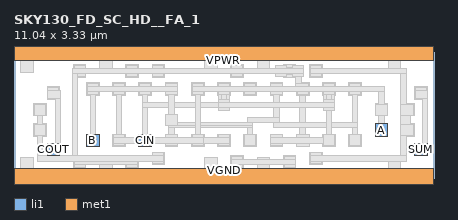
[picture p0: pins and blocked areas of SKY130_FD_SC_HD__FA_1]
MACRO SKY130_FD_SC_HD__FA_1
 CLASS CORE ;
 FOREIGN SKY130_FD_SC_HD__FA_1 0 0 ;
 SIZE 11.040000000000001 BY 3.33 ;
 ORIGIN 0 0 ;
 SYMMETRY X Y R90 ;
 SITE unit ;
  PIN VPWR
   DIRECTION INOUT ;
   USE POWER ;
   SHAPE ABUTMENT ;
    PORT
     CLASS CORE ;
       LAYER li1 ;
        RECT 0.00000000 3.09000000 11.04000000 3.57000000 ;
       LAYER met1 ;
        RECT 0.00000000 3.09000000 11.04000000 3.57000000 ;
    END
  END VPWR

  PIN VGND
   DIRECTION INOUT ;
   USE POWER ;
   SHAPE ABUTMENT ;
    PORT
     CLASS CORE ;
       LAYER li1 ;
        RECT 0.00000000 -0.24000000 11.04000000 0.24000000 ;
       LAYER met1 ;
        RECT 0.00000000 -0.24000000 11.04000000 0.24000000 ;
    END
  END VGND

  PIN COUT
   DIRECTION INOUT ;
   USE SIGNAL ;
   SHAPE ABUTMENT ;
    PORT
     CLASS CORE ;
       LAYER li1 ;
        RECT 0.87000000 0.58000000 1.20000000 0.91000000 ;
    END
  END COUT

  PIN SUM
   DIRECTION INOUT ;
   USE SIGNAL ;
   SHAPE ABUTMENT ;
    PORT
     CLASS CORE ;
       LAYER li1 ;
        RECT 10.53000000 0.58000000 10.86000000 0.91000000 ;
    END
  END SUM

  PIN A
   DIRECTION INOUT ;
   USE SIGNAL ;
   SHAPE ABUTMENT ;
    PORT
     CLASS CORE ;
       LAYER li1 ;
        RECT 9.49500000 1.09500000 9.82500000 1.42500000 ;
    END
  END A

  PIN B
   DIRECTION INOUT ;
   USE SIGNAL ;
   SHAPE ABUTMENT ;
    PORT
     CLASS CORE ;
       LAYER li1 ;
        RECT 1.90500000 0.82500000 2.23500000 1.15500000 ;
    END
  END B

  PIN CIN
   DIRECTION INOUT ;
   USE SIGNAL ;
   SHAPE ABUTMENT ;
    PORT
     CLASS CORE ;
       LAYER li1 ;
        RECT 3.28500000 0.82500000 3.61500000 1.15500000 ;
    END
  END CIN

 OBS
    LAYER polycont ;
     RECT 3.36500000 0.90500000 3.53500000 1.07500000 ;
     RECT 6.81500000 0.90500000 6.98500000 1.07500000 ;
     RECT 8.19500000 0.90500000 8.36500000 1.07500000 ;
     RECT 3.36500000 2.25500000 3.53500000 2.42500000 ;
     RECT 5.43500000 2.25500000 5.60500000 2.42500000 ;
     RECT 8.19500000 2.25500000 8.36500000 2.42500000 ;
     RECT 1.98500000 0.90500000 2.15500000 1.07500000 ;
     RECT 4.05500000 0.90500000 4.22500000 1.07500000 ;
     RECT 6.12500000 0.90500000 6.29500000 1.07500000 ;
     RECT 8.88500000 0.90500000 9.05500000 1.07500000 ;
     RECT 1.98500000 2.25500000 2.15500000 2.42500000 ;
     RECT 4.05500000 2.25500000 4.22500000 2.42500000 ;
     RECT 6.81500000 2.25500000 6.98500000 2.42500000 ;
     RECT 8.88500000 2.25500000 9.05500000 2.42500000 ;
     RECT 7.50500000 0.90500000 7.67500000 1.07500000 ;
     RECT 0.60500000 1.17500000 0.77500000 1.34500000 ;
     RECT 0.60500000 1.71500000 0.77500000 1.88500000 ;
     RECT 7.50500000 2.25500000 7.67500000 2.42500000 ;
     RECT 10.26500000 1.17500000 10.43500000 1.34500000 ;
     RECT 10.26500000 1.71500000 10.43500000 1.88500000 ;
     RECT 2.67500000 0.90500000 2.84500000 1.07500000 ;
     RECT 4.74500000 0.90500000 4.91500000 1.07500000 ;
     RECT 5.43500000 0.90500000 5.60500000 1.07500000 ;
     RECT 9.57500000 1.17500000 9.74500000 1.34500000 ;
     RECT 9.57500000 1.71500000 9.74500000 1.88500000 ;
     RECT 2.67500000 2.25500000 2.84500000 2.42500000 ;
     RECT 4.74500000 2.25500000 4.91500000 2.42500000 ;
     RECT 6.12500000 2.25500000 6.29500000 2.42500000 ;

    LAYER pdiffc ;
     RECT 0.95000000 2.15000000 1.12000000 2.32000000 ;
     RECT 3.71000000 2.73000000 3.88000000 2.90000000 ;
     RECT 7.85000000 2.73000000 8.02000000 2.90000000 ;
     RECT 0.26000000 2.86000000 0.43000000 3.03000000 ;
     RECT 2.33000000 2.86000000 2.50000000 3.03000000 ;
     RECT 5.09000000 2.86000000 5.26000000 3.03000000 ;
     RECT 6.47000000 2.86000000 6.64000000 3.03000000 ;
     RECT 9.92000000 2.86000000 10.09000000 3.03000000 ;
     RECT 1.64000000 2.73000000 1.81000000 2.90000000 ;
     RECT 3.02000000 2.73000000 3.19000000 2.90000000 ;
     RECT 10.61000000 2.15000000 10.78000000 2.32000000 ;
     RECT 5.78000000 2.73000000 5.95000000 2.90000000 ;
     RECT 7.16000000 2.73000000 7.33000000 2.90000000 ;

    LAYER ndiffc ;
     RECT 0.95000000 0.66000000 1.12000000 0.83000000 ;
     RECT 3.71000000 0.43000000 3.88000000 0.60000000 ;
     RECT 7.85000000 0.43000000 8.02000000 0.60000000 ;
     RECT 5.78000000 0.34000000 5.95000000 0.51000000 ;
     RECT 7.16000000 0.34000000 7.33000000 0.51000000 ;
     RECT 0.26000000 0.30000000 0.43000000 0.47000000 ;
     RECT 2.33000000 0.30000000 2.50000000 0.47000000 ;
     RECT 5.09000000 0.30000000 5.26000000 0.47000000 ;
     RECT 6.47000000 0.30000000 6.64000000 0.47000000 ;
     RECT 9.92000000 0.30000000 10.09000000 0.47000000 ;
     RECT 1.64000000 0.34000000 1.81000000 0.51000000 ;
     RECT 3.02000000 0.34000000 3.19000000 0.51000000 ;
     RECT 10.61000000 0.66000000 10.78000000 0.83000000 ;

    LAYER li1 ;
     RECT 3.28500000 0.82500000 3.61500000 1.15500000 ;
     RECT 6.73500000 0.82500000 7.06500000 1.15500000 ;
     RECT 8.11500000 0.82500000 8.44500000 1.15500000 ;
     RECT 3.28500000 2.17500000 3.61500000 2.50500000 ;
     RECT 5.35500000 2.17500000 5.68500000 2.50500000 ;
     RECT 8.11500000 2.17500000 8.44500000 2.50500000 ;
     RECT 1.90500000 0.82500000 2.23500000 1.15500000 ;
     RECT 3.97500000 0.82500000 4.30500000 1.15500000 ;
     RECT 6.04500000 0.82500000 6.37500000 1.15500000 ;
     RECT 8.80500000 0.82500000 9.13500000 1.15500000 ;
     RECT 1.90500000 2.17500000 2.23500000 2.50500000 ;
     RECT 3.97500000 2.17500000 4.30500000 2.50500000 ;
     RECT 6.73500000 2.17500000 7.06500000 2.50500000 ;
     RECT 8.80500000 2.17500000 9.13500000 2.50500000 ;
     RECT 0.87000000 0.58000000 1.20000000 0.91000000 ;
     RECT 0.87000000 2.07000000 1.20000000 2.40000000 ;
     RECT 3.63000000 0.35000000 3.96000000 0.68000000 ;
     RECT 0.52500000 1.09500000 0.85500000 1.42500000 ;
     RECT 0.52500000 1.63500000 0.85500000 1.96500000 ;
     RECT 7.42500000 0.82500000 7.75500000 1.15500000 ;
     RECT 7.50500000 1.15500000 7.67500000 2.17500000 ;
     RECT 7.42500000 2.17500000 7.75500000 2.50500000 ;
     RECT 3.63000000 2.65000000 3.96000000 2.98000000 ;
     RECT 7.77000000 0.35000000 8.10000000 0.68000000 ;
     RECT 10.18500000 1.09500000 10.51500000 1.42500000 ;
     RECT 10.18500000 1.63500000 10.51500000 1.96500000 ;
     RECT 7.77000000 2.65000000 8.10000000 2.98000000 ;
     RECT 0.18000000 2.78000000 0.51000000 3.09000000 ;
     RECT 2.25000000 2.78000000 2.58000000 3.09000000 ;
     RECT 5.01000000 2.78000000 5.34000000 3.09000000 ;
     RECT 6.39000000 2.78000000 6.72000000 3.09000000 ;
     RECT 9.84000000 2.78000000 10.17000000 3.09000000 ;
     RECT 0.00000000 3.09000000 11.04000000 3.57000000 ;
     RECT 5.70000000 0.26000000 6.03000000 0.59000000 ;
     RECT 7.08000000 0.26000000 7.41000000 0.59000000 ;
     RECT 1.56000000 2.65000000 1.89000000 2.98000000 ;
     RECT 2.94000000 2.65000000 3.27000000 2.98000000 ;
     RECT 0.00000000 -0.24000000 11.04000000 0.24000000 ;
     RECT 0.18000000 0.24000000 0.51000000 0.55000000 ;
     RECT 2.25000000 0.24000000 2.58000000 0.55000000 ;
     RECT 5.01000000 0.24000000 5.34000000 0.55000000 ;
     RECT 6.39000000 0.24000000 6.72000000 0.55000000 ;
     RECT 9.84000000 0.24000000 10.17000000 0.55000000 ;
     RECT 1.56000000 0.26000000 1.89000000 0.59000000 ;
     RECT 2.94000000 0.26000000 3.27000000 0.59000000 ;
     RECT 10.53000000 0.58000000 10.86000000 0.91000000 ;
     RECT 10.53000000 2.07000000 10.86000000 2.40000000 ;
     RECT 5.70000000 2.65000000 6.03000000 2.98000000 ;
     RECT 7.08000000 2.65000000 7.41000000 2.73000000 ;
     RECT 6.93000000 2.73000000 7.41000000 2.90000000 ;
     RECT 7.08000000 2.90000000 7.41000000 2.98000000 ;
     RECT 2.59500000 0.82500000 2.92500000 1.15500000 ;
     RECT 4.66500000 0.82500000 4.99500000 1.15500000 ;
     RECT 5.35500000 0.82500000 5.68500000 1.15500000 ;
     RECT 9.49500000 1.09500000 9.82500000 1.42500000 ;
     RECT 9.49500000 1.63500000 9.82500000 1.96500000 ;
     RECT 2.59500000 2.17500000 2.92500000 2.50500000 ;
     RECT 4.66500000 2.17500000 4.99500000 2.50500000 ;
     RECT 6.04500000 2.17500000 6.37500000 2.50500000 ;

    LAYER viali ;
     RECT 3.36500000 0.90500000 3.53500000 1.07500000 ;
     RECT 6.81500000 0.90500000 6.98500000 1.07500000 ;
     RECT 8.19500000 0.90500000 8.36500000 1.07500000 ;
     RECT 3.36500000 2.25500000 3.53500000 2.42500000 ;
     RECT 5.43500000 2.25500000 5.60500000 2.42500000 ;
     RECT 8.19500000 2.25500000 8.36500000 2.42500000 ;
     RECT 1.98500000 0.90500000 2.15500000 1.07500000 ;
     RECT 4.05500000 0.90500000 4.22500000 1.07500000 ;
     RECT 6.12500000 0.90500000 6.29500000 1.07500000 ;
     RECT 8.88500000 0.90500000 9.05500000 1.07500000 ;
     RECT 1.98500000 2.25500000 2.15500000 2.42500000 ;
     RECT 4.05500000 2.25500000 4.22500000 2.42500000 ;
     RECT 6.81500000 2.25500000 6.98500000 2.42500000 ;
     RECT 8.88500000 2.25500000 9.05500000 2.42500000 ;
     RECT 0.95000000 0.66000000 1.12000000 0.83000000 ;
     RECT 0.95000000 2.15000000 1.12000000 2.32000000 ;
     RECT 3.71000000 0.43000000 3.88000000 0.60000000 ;
     RECT 0.60500000 1.17500000 0.77500000 1.34500000 ;
     RECT 0.60500000 1.71500000 0.77500000 1.88500000 ;
     RECT 7.50500000 2.25500000 7.67500000 2.42500000 ;
     RECT 3.71000000 2.73000000 3.88000000 2.90000000 ;
     RECT 7.85000000 0.43000000 8.02000000 0.60000000 ;
     RECT 10.26500000 1.17500000 10.43500000 1.34500000 ;
     RECT 10.26500000 1.71500000 10.43500000 1.88500000 ;
     RECT 7.85000000 2.73000000 8.02000000 2.90000000 ;
     RECT 2.33000000 3.24500000 2.50000000 3.41500000 ;
     RECT 5.78000000 0.34000000 5.95000000 0.51000000 ;
     RECT 7.16000000 0.34000000 7.33000000 0.51000000 ;
     RECT 1.64000000 2.73000000 1.81000000 2.90000000 ;
     RECT 3.02000000 2.73000000 3.19000000 2.90000000 ;
     RECT 6.47000000 -0.08500000 6.64000000 0.08500000 ;
     RECT 1.64000000 0.34000000 1.81000000 0.51000000 ;
     RECT 3.02000000 0.34000000 3.19000000 0.51000000 ;
     RECT 10.61000000 0.66000000 10.78000000 0.83000000 ;
     RECT 10.61000000 2.15000000 10.78000000 2.32000000 ;
     RECT 5.78000000 2.73000000 5.95000000 2.90000000 ;
     RECT 6.93000000 2.73000000 7.10000000 2.90000000 ;
     RECT 2.67500000 0.90500000 2.84500000 1.07500000 ;
     RECT 4.74500000 0.90500000 4.91500000 1.07500000 ;
     RECT 5.43500000 0.90500000 5.60500000 1.07500000 ;
     RECT 9.57500000 1.17500000 9.74500000 1.34500000 ;
     RECT 9.57500000 1.71500000 9.74500000 1.88500000 ;
     RECT 2.67500000 2.25500000 2.84500000 2.42500000 ;
     RECT 4.74500000 2.25500000 4.91500000 2.42500000 ;
     RECT 6.12500000 2.25500000 6.29500000 2.42500000 ;

    LAYER met1 ;
     RECT 3.38000000 1.13500000 3.52000000 1.85500000 ;
     RECT 5.37500000 1.78000000 5.66500000 1.85500000 ;
     RECT 3.38000000 1.85500000 5.66500000 1.99500000 ;
     RECT 5.37500000 1.99500000 5.66500000 2.07000000 ;
     RECT 5.45000000 2.07000000 5.59000000 2.19500000 ;
     RECT 5.37500000 2.19500000 5.66500000 2.48500000 ;
     RECT 2.00000000 1.13500000 2.14000000 2.19500000 ;
     RECT 4.07000000 1.32500000 6.28000000 1.38500000 ;
     RECT 3.99500000 1.38500000 6.28000000 1.46000000 ;
     RECT 3.99500000 1.46000000 9.04000000 1.46500000 ;
     RECT 3.99500000 1.46500000 4.28500000 1.67500000 ;
     RECT 6.83000000 1.60000000 6.97000000 2.19500000 ;
     RECT 8.90000000 1.46500000 9.04000000 2.19500000 ;
     RECT 1.08000000 0.89000000 1.22000000 2.09000000 ;
     RECT 0.54500000 1.65500000 0.83500000 1.94500000 ;
     RECT 10.16500000 1.65500000 10.49500000 1.94500000 ;
     RECT 0.00000000 3.09000000 11.04000000 3.57000000 ;
     RECT 0.00000000 -0.24000000 11.04000000 0.24000000 ;
     RECT 10.74000000 0.89000000 10.88000000 2.09000000 ;
     RECT 5.37500000 0.84500000 5.66500000 0.92000000 ;
     RECT 4.68500000 0.92000000 5.66500000 1.06000000 ;
     RECT 5.37500000 1.06000000 5.66500000 1.13500000 ;
     RECT 9.51500000 1.65500000 9.80500000 1.94500000 ;
     RECT 2.69000000 1.13500000 2.83000000 2.19500000 ;
     RECT 7.40500000 2.27000000 7.73500000 2.48500000 ;
     RECT 7.40500000 2.48500000 7.54500000 2.67000000 ;
     RECT 7.33000000 2.67000000 7.62000000 2.96000000 ;
     RECT 8.13500000 1.78000000 8.42500000 2.07000000 ;
     RECT 7.79000000 2.67000000 8.08000000 2.74500000 ;
     RECT 10.16500000 1.94500000 10.30500000 2.74500000 ;
     RECT 7.79000000 2.74500000 10.30500000 2.88500000 ;
     RECT 7.79000000 2.88500000 8.08000000 2.96000000 ;
     RECT 8.21000000 2.07000000 8.35000000 2.19500000 ;
     RECT 8.13500000 2.19500000 8.42500000 2.48500000 ;
     RECT 5.59000000 2.07000000 5.66500000 2.19500000 ;
     RECT 10.55000000 2.09000000 10.88000000 2.30500000 ;
     RECT 10.55000000 2.30500000 10.84000000 2.38000000 ;
     RECT 5.72000000 2.67000000 6.01000000 2.74500000 ;
     RECT 6.87000000 2.67000000 7.16000000 2.74500000 ;
     RECT 5.72000000 2.74500000 7.16000000 2.88500000 ;
     RECT 5.72000000 2.88500000 6.01000000 2.96000000 ;
     RECT 6.87000000 2.88500000 7.16000000 2.96000000 ;
     RECT 6.75500000 2.19500000 7.04500000 2.48500000 ;
     RECT 8.82500000 2.19500000 9.11500000 2.48500000 ;
     RECT 8.13500000 2.07000000 8.21000000 2.19500000 ;
     RECT 8.35000000 2.07000000 8.42500000 2.19500000 ;
     RECT 7.44500000 2.19500000 7.73500000 2.27000000 ;
     RECT 6.06500000 2.19500000 6.35500000 2.48500000 ;
     RECT 0.89000000 2.09000000 1.22000000 2.30500000 ;
     RECT 0.89000000 2.30500000 1.18000000 2.38000000 ;
     RECT 3.99500000 2.19500000 4.28500000 2.48500000 ;
     RECT 3.65000000 2.67000000 3.94000000 2.96000000 ;
     RECT 3.30500000 2.19500000 3.59500000 2.48500000 ;
     RECT 3.38000000 1.99500000 3.52000000 2.19500000 ;
     RECT 1.58000000 2.67000000 1.87000000 2.74500000 ;
     RECT 2.96000000 2.67000000 3.25000000 2.74500000 ;
     RECT 1.58000000 2.74500000 3.25000000 2.88500000 ;
     RECT 1.58000000 2.88500000 1.87000000 2.96000000 ;
     RECT 2.96000000 2.88500000 3.25000000 2.96000000 ;
     RECT 5.37500000 2.07000000 5.45000000 2.19500000 ;
     RECT 2.61500000 2.19500000 2.90500000 2.48500000 ;
     RECT 4.68500000 2.19500000 4.97500000 2.48500000 ;
     RECT 1.92500000 2.19500000 2.21500000 2.48500000 ;
     RECT 0.89000000 0.67500000 1.22000000 0.89000000 ;
     RECT 1.92500000 0.84500000 2.21500000 1.13500000 ;
     RECT 3.30500000 0.84500000 3.59500000 1.13500000 ;
     RECT 3.99500000 0.84500000 4.28500000 1.13500000 ;
     RECT 3.65000000 0.37000000 3.94000000 0.66000000 ;
     RECT 0.54500000 1.11500000 0.83500000 1.40500000 ;
     RECT 4.68500000 0.84500000 4.97500000 0.92000000 ;
     RECT 0.62000000 1.40500000 0.76000000 1.65500000 ;
     RECT 1.58000000 0.28000000 1.87000000 0.35500000 ;
     RECT 4.68500000 1.06000000 4.97500000 1.13500000 ;
     RECT 2.96000000 0.28000000 3.25000000 0.35500000 ;
     RECT 1.58000000 0.35500000 3.25000000 0.49500000 ;
     RECT 2.61500000 0.84500000 2.90500000 1.13500000 ;
     RECT 1.58000000 0.49500000 1.87000000 0.57000000 ;
     RECT 2.96000000 0.49500000 3.25000000 0.57000000 ;
     RECT 4.07000000 1.13500000 4.21000000 1.32500000 ;
     RECT 0.89000000 0.60000000 1.18000000 0.67500000 ;
     RECT 10.16500000 0.58500000 10.30500000 1.11500000 ;
     RECT 10.16500000 1.11500000 10.49500000 1.40500000 ;
     RECT 10.16500000 1.40500000 10.42000000 1.65500000 ;
     RECT 10.55000000 0.60000000 10.84000000 0.67500000 ;
     RECT 10.55000000 0.67500000 10.88000000 0.89000000 ;
     RECT 6.83000000 1.32500000 9.04000000 1.46000000 ;
     RECT 6.75500000 0.84500000 7.04500000 0.92000000 ;
     RECT 6.14000000 1.46500000 6.97000000 1.60000000 ;
     RECT 8.13500000 0.84500000 8.42500000 0.92000000 ;
     RECT 6.06500000 0.84500000 6.35500000 1.13500000 ;
     RECT 8.82500000 0.84500000 9.11500000 1.13500000 ;
     RECT 5.72000000 0.28000000 6.01000000 0.35500000 ;
     RECT 7.10000000 0.28000000 7.39000000 0.35500000 ;
     RECT 5.72000000 0.35500000 7.39000000 0.49500000 ;
     RECT 5.72000000 0.49500000 6.01000000 0.57000000 ;
     RECT 7.10000000 0.49500000 7.39000000 0.57000000 ;
     RECT 6.75500000 0.92000000 8.42500000 1.06000000 ;
     RECT 6.14000000 1.13500000 6.28000000 1.32500000 ;
     RECT 9.51500000 1.11500000 9.80500000 1.40500000 ;
     RECT 9.59000000 1.40500000 9.73000000 1.65500000 ;
     RECT 8.90000000 1.13500000 9.04000000 1.32500000 ;
     RECT 6.75500000 1.06000000 7.04500000 1.13500000 ;
     RECT 8.13500000 1.06000000 8.42500000 1.13500000 ;
     RECT 7.79000000 0.37000000 8.08000000 0.44500000 ;
     RECT 7.79000000 0.44500000 10.30500000 0.58500000 ;
     RECT 7.79000000 0.58500000 8.08000000 0.66000000 ;

    LAYER via ;
     RECT 8.19500000 0.90500000 8.36500000 1.07500000 ;
     RECT 5.43500000 1.84000000 5.60500000 2.01000000 ;
     RECT 8.19500000 1.84000000 8.36500000 2.01000000 ;
     RECT 4.05500000 1.44500000 4.22500000 1.61500000 ;
     RECT 1.98500000 2.25500000 2.15500000 2.42500000 ;
     RECT 4.05500000 2.25500000 4.22500000 2.42500000 ;
     RECT 3.71000000 0.43000000 3.88000000 0.60000000 ;
     RECT 0.60500000 1.17500000 0.77500000 1.34500000 ;
     RECT 3.71000000 2.73000000 3.88000000 2.90000000 ;
     RECT 7.39000000 2.73000000 7.56000000 2.90000000 ;
     RECT 2.67500000 0.90500000 2.84500000 1.07500000 ;
     RECT 4.74500000 0.90500000 4.91500000 1.07500000 ;
     RECT 9.57500000 1.71500000 9.74500000 1.88500000 ;
     RECT 4.74500000 2.25500000 4.91500000 2.42500000 ;
     RECT 6.12500000 2.25500000 6.29500000 2.42500000 ;

    LAYER met2 ;
     RECT 8.13500000 0.84500000 8.42500000 1.13500000 ;
     RECT 8.21000000 1.13500000 8.35000000 1.78000000 ;
     RECT 5.37500000 1.78000000 5.66500000 1.85500000 ;
     RECT 8.13500000 1.78000000 8.42500000 1.85500000 ;
     RECT 5.37500000 1.85500000 8.42500000 1.99500000 ;
     RECT 5.37500000 1.99500000 5.66500000 2.07000000 ;
     RECT 8.13500000 1.99500000 8.42500000 2.07000000 ;
     RECT 3.99500000 1.38500000 4.28500000 1.67500000 ;
     RECT 4.07000000 1.67500000 4.21000000 2.19500000 ;
     RECT 1.92500000 2.19500000 2.21500000 2.27000000 ;
     RECT 3.99500000 2.19500000 4.28500000 2.27000000 ;
     RECT 1.92500000 2.27000000 4.28500000 2.41000000 ;
     RECT 1.92500000 2.41000000 2.21500000 2.48500000 ;
     RECT 3.99500000 2.41000000 4.28500000 2.48500000 ;
     RECT 3.65000000 0.37000000 3.94000000 0.44500000 ;
     RECT 0.62000000 0.44500000 3.94000000 0.58500000 ;
     RECT 3.65000000 0.58500000 3.94000000 0.66000000 ;
     RECT 0.62000000 0.58500000 0.76000000 1.11500000 ;
     RECT 0.54500000 1.11500000 0.83500000 1.40500000 ;
     RECT 1.54000000 0.58500000 1.68000000 2.74500000 ;
     RECT 3.65000000 2.67000000 3.94000000 2.74500000 ;
     RECT 7.33000000 2.67000000 7.62000000 2.74500000 ;
     RECT 1.54000000 2.74500000 7.62000000 2.88500000 ;
     RECT 3.65000000 2.88500000 3.94000000 2.96000000 ;
     RECT 7.33000000 2.88500000 7.62000000 2.96000000 ;
     RECT 2.61500000 0.84500000 2.90500000 0.92000000 ;
     RECT 4.68500000 0.84500000 4.97500000 0.92000000 ;
     RECT 2.61500000 0.92000000 4.97500000 1.06000000 ;
     RECT 2.61500000 1.06000000 2.90500000 1.13500000 ;
     RECT 4.68500000 1.06000000 4.97500000 1.13500000 ;
     RECT 9.51500000 1.65500000 9.80500000 1.94500000 ;
     RECT 4.76000000 1.13500000 4.90000000 2.19500000 ;
     RECT 4.68500000 2.19500000 4.97500000 2.27000000 ;
     RECT 6.06500000 2.19500000 6.35500000 2.27000000 ;
     RECT 9.59000000 1.94500000 9.73000000 2.27000000 ;
     RECT 4.68500000 2.27000000 9.73000000 2.41000000 ;
     RECT 4.68500000 2.41000000 4.97500000 2.48500000 ;
     RECT 6.06500000 2.41000000 6.35500000 2.48500000 ;

    LAYER via2 ;


    LAYER met3 ;


 END
END SKY130_FD_SC_HD__FA_1
